VERSION 5.8 ;
BUSBITCHARS "[]" ;
DIVIDERCHAR "/" ;
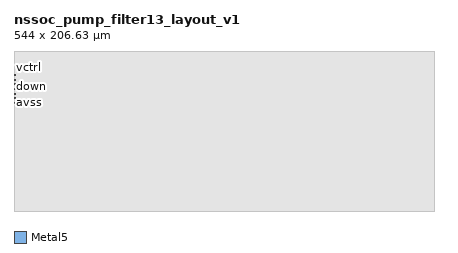
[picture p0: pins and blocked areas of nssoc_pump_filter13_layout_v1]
MACRO nssoc_pump_filter13_layout_v1
  CLASS BLOCK ;
  ORIGIN 0 0 ;
  SIZE 544.000 BY 206.630 ;
  PIN up
    DIRECTION INPUT ;
    USE SIGNAL ;
    PORT
      LAYER Metal5 ;
      RECT 0.000 163.430 2.000 164.630 ;
    END
  END up
  PIN down
    DIRECTION INPUT ;
    USE SIGNAL ;
    PORT
      LAYER Metal5 ;
      RECT 0.000 151.430 2.000 152.630 ;
    END
  END down
  PIN vctrl
    DIRECTION INOUT ;
    USE SIGNAL ;
    PORT
      LAYER Metal5 ;
      RECT 0.000 175.430 2.000 176.630 ;
    END
  END vctrl
  PIN vco_avdd
    DIRECTION INOUT ;
    USE POWER ;
    PORT
      LAYER Metal5 ;
      RECT 0.000 169.430 2.000 170.630 ;
    END
  END vco_avdd
  PIN div_avdd
    DIRECTION INOUT ;
    USE POWER ;
    PORT
      LAYER Metal5 ;
      RECT 0.000 145.430 2.000 146.630 ;
    END
  END div_avdd
  PIN avss
    DIRECTION INOUT ;
    USE GROUND ;
    PORT
      LAYER Metal5 ;
      RECT 0.000 139.430 2.000 140.630 ;
    END
  END avss
  PIN sub
    DIRECTION INOUT ;
    USE GROUND ;
    PORT
      LAYER Metal5 ;
      RECT 0.000 157.430 2.000 158.630 ;
    END
  END sub
  OBS
    LAYER Metal1 ;
      RECT 0.000 0.000 544.000 206.630 ;
    LAYER Metal2 ;
      RECT 0.000 0.000 544.000 206.630 ;
    LAYER Metal3 ;
      RECT 0.000 0.000 544.000 206.630 ;
    LAYER Metal4 ;
      RECT 0.000 0.000 544.000 206.630 ;
    LAYER Metal5 ;
      RECT 0.000 0.000 544.000 139.430 ;
      RECT 2.000 139.430 544.000 140.630 ;
      RECT 0.000 140.630 544.000 145.430 ;
      RECT 2.000 145.430 544.000 146.630 ;
      RECT 0.000 146.630 544.000 151.430 ;
      RECT 2.000 151.430 544.000 152.630 ;
      RECT 0.000 152.630 544.000 157.430 ;
      RECT 2.000 157.430 544.000 158.630 ;
      RECT 0.000 158.630 544.000 163.430 ;
      RECT 2.000 163.430 544.000 164.630 ;
      RECT 0.000 164.630 544.000 169.430 ;
      RECT 2.000 169.430 544.000 170.630 ;
      RECT 0.000 170.630 544.000 175.430 ;
      RECT 2.000 175.430 544.000 176.630 ;
      RECT 0.000 176.630 544.000 206.630 ;
    LAYER TopMetal1 ;
      RECT 0.000 0.000 544.000 206.630 ;
    LAYER TopMetal2 ;
      RECT 0.000 0.000 544.000 206.630 ;
  END
END nssoc_pump_filter13_layout_v1
END LIBRARY
